VERSION 5.8 ;
BUSBITCHARS "[]" ;
DIVIDERCHAR "/" ;
UNITS
    DATABASE MICRONS 1000 ;
END UNITS

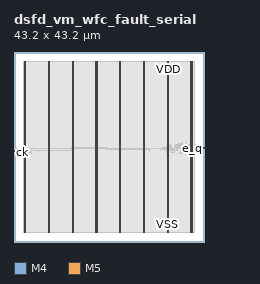
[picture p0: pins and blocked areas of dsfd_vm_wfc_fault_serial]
MACRO dsfd_vm_wfc_fault_serial
  FOREIGN dsfd_vm_wfc_fault_serial 0 0 ;
  CLASS BLOCK ;
  SIZE 43.2 BY 43.2 ;
  PIN ck
    DIRECTION INPUT ;
    USE SIGNAL ;
    PORT
      LAYER M4 ;
        RECT  0 20.4 0.084 20.424 ;
    END
  END ck
  PIN e_q
    DIRECTION OUTPUT ;
    USE SIGNAL ;
    PORT
      LAYER M4 ;
        RECT  43.116 21.36 43.2 21.384 ;
    END
  END e_q
  PIN g_q
    DIRECTION OUTPUT ;
    USE SIGNAL ;
    PORT
      LAYER M4 ;
        RECT  43.116 21.456 43.2 21.48 ;
    END
  END g_q
  PIN remote_fault
    DIRECTION INPUT ;
    USE SIGNAL ;
    PORT
      LAYER M4 ;
        RECT  0 20.496 0.084 20.52 ;
    END
  END remote_fault
  PIN rn
    DIRECTION INPUT ;
    USE SIGNAL ;
    PORT
      LAYER M4 ;
        RECT  0 20.592 0.084 20.616 ;
    END
  END rn
  PIN serial_fault
    DIRECTION INPUT ;
    USE SIGNAL ;
    PORT
      LAYER M4 ;
        RECT  0 20.688 0.084 20.712 ;
    END
  END serial_fault
  PIN source_fault
    DIRECTION OUTPUT ;
    USE SIGNAL ;
    PORT
      LAYER M4 ;
        RECT  43.116 21.552 43.2 21.576 ;
    END
  END source_fault
  PIN transfer_fault
    DIRECTION INPUT ;
    USE SIGNAL ;
    PORT
      LAYER M4 ;
        RECT  0 20.784 0.084 20.808 ;
    END
  END transfer_fault
  PIN VDD
    DIRECTION INOUT ;
    USE POWER ;
    PORT
      LAYER M5 ;
        RECT  40.392 2.151 40.512 41.049 ;
        RECT  34.992 2.151 35.112 41.049 ;
        RECT  29.592 2.151 29.712 41.049 ;
        RECT  24.192 2.151 24.312 41.049 ;
        RECT  18.792 2.151 18.912 41.049 ;
        RECT  13.392 2.151 13.512 41.049 ;
        RECT  7.992 2.151 8.112 41.049 ;
        RECT  2.592 2.151 2.712 41.049 ;
    END
  END VDD
  PIN VSS
    DIRECTION INOUT ;
    USE GROUND ;
    PORT
      LAYER M5 ;
        RECT  40.2 2.137 40.32 41.063 ;
        RECT  34.8 2.137 34.92 41.063 ;
        RECT  29.4 2.137 29.52 41.063 ;
        RECT  24 2.137 24.12 41.063 ;
        RECT  18.6 2.137 18.72 41.063 ;
        RECT  13.2 2.137 13.32 41.063 ;
        RECT  7.8 2.137 7.92 41.063 ;
        RECT  2.4 2.137 2.52 41.063 ;
    END
  END VSS
  # OT_OBS_CLOSED layer=M5 d_um=1.536 added=0
  OBS
    LAYER RVTN ;
     RECT  2.16 2.16 41.04 2.295 ;
     RECT  2.16 2.565 41.04 2.835 ;
     RECT  2.16 3.105 41.04 3.375 ;
     RECT  2.16 3.645 41.04 3.915 ;
     RECT  2.16 4.185 41.04 4.455 ;
     RECT  2.16 4.725 41.04 4.995 ;
     RECT  2.16 5.265 41.04 5.535 ;
     RECT  2.16 5.805 41.04 6.075 ;
     RECT  2.16 6.345 41.04 6.615 ;
     RECT  2.16 6.885 41.04 7.155 ;
     RECT  2.16 7.425 41.04 7.695 ;
     RECT  2.16 7.965 41.04 8.235 ;
     RECT  2.16 8.505 41.04 8.775 ;
     RECT  2.16 9.045 41.04 9.315 ;
     RECT  2.16 9.585 41.04 9.855 ;
     RECT  2.16 10.125 41.04 10.395 ;
     RECT  2.16 10.665 41.04 10.935 ;
     RECT  2.16 11.205 41.04 11.475 ;
     RECT  2.16 11.745 41.04 12.015 ;
     RECT  2.16 12.285 41.04 12.555 ;
     RECT  2.16 12.825 41.04 13.095 ;
     RECT  2.16 13.365 41.04 13.635 ;
     RECT  2.16 13.905 41.04 14.175 ;
     RECT  2.16 14.445 41.04 14.715 ;
     RECT  2.16 14.985 41.04 15.255 ;
     RECT  2.16 15.525 41.04 15.795 ;
     RECT  2.16 16.065 41.04 16.335 ;
     RECT  2.16 16.605 41.04 16.875 ;
     RECT  2.16 17.145 41.04 17.415 ;
     RECT  2.16 17.685 41.04 17.955 ;
     RECT  2.16 18.225 41.04 18.495 ;
     RECT  2.16 18.765 41.04 19.035 ;
     RECT  2.16 19.305 41.04 19.575 ;
     RECT  2.16 19.845 41.04 20.115 ;
     RECT  2.16 20.385 41.04 20.655 ;
     RECT  2.16 20.925 41.04 21.195 ;
     RECT  2.16 21.465 41.04 21.735 ;
     RECT  2.16 22.005 41.04 22.275 ;
     RECT  2.16 22.545 41.04 22.815 ;
     RECT  2.16 23.085 41.04 23.355 ;
     RECT  2.16 23.625 41.04 23.895 ;
     RECT  2.16 24.165 41.04 24.435 ;
     RECT  2.16 24.705 41.04 24.975 ;
     RECT  2.16 25.245 41.04 25.515 ;
     RECT  2.16 25.785 41.04 26.055 ;
     RECT  2.16 26.325 41.04 26.595 ;
     RECT  2.16 26.865 41.04 27.135 ;
     RECT  2.16 27.405 41.04 27.675 ;
     RECT  2.16 27.945 41.04 28.215 ;
     RECT  2.16 28.485 41.04 28.755 ;
     RECT  2.16 29.025 41.04 29.295 ;
     RECT  2.16 29.565 41.04 29.835 ;
     RECT  2.16 30.105 41.04 30.375 ;
     RECT  2.16 30.645 41.04 30.915 ;
     RECT  2.16 31.185 41.04 31.455 ;
     RECT  2.16 31.725 41.04 31.995 ;
     RECT  2.16 32.265 41.04 32.535 ;
     RECT  2.16 32.805 41.04 33.075 ;
     RECT  2.16 33.345 41.04 33.615 ;
     RECT  2.16 33.885 41.04 34.155 ;
     RECT  2.16 34.425 41.04 34.695 ;
     RECT  2.16 34.965 41.04 35.235 ;
     RECT  2.16 35.505 41.04 35.775 ;
     RECT  2.16 36.045 41.04 36.315 ;
     RECT  2.16 36.585 41.04 36.855 ;
     RECT  2.16 37.125 41.04 37.395 ;
     RECT  2.16 37.665 41.04 37.935 ;
     RECT  2.16 38.205 41.04 38.475 ;
     RECT  2.16 38.745 41.04 39.015 ;
     RECT  2.16 39.285 41.04 39.555 ;
     RECT  2.16 39.825 41.04 40.095 ;
     RECT  2.16 40.365 41.04 40.635 ;
     RECT  2.16 40.905 41.04 41.04 ;
    LAYER RVTP ;
     RECT  2.16 2.295 41.04 2.565 ;
     RECT  2.16 2.835 41.04 3.105 ;
     RECT  2.16 3.375 41.04 3.645 ;
     RECT  2.16 3.915 41.04 4.185 ;
     RECT  2.16 4.455 41.04 4.725 ;
     RECT  2.16 4.995 41.04 5.265 ;
     RECT  2.16 5.535 41.04 5.805 ;
     RECT  2.16 6.075 41.04 6.345 ;
     RECT  2.16 6.615 41.04 6.885 ;
     RECT  2.16 7.155 41.04 7.425 ;
     RECT  2.16 7.695 41.04 7.965 ;
     RECT  2.16 8.235 41.04 8.505 ;
     RECT  2.16 8.775 41.04 9.045 ;
     RECT  2.16 9.315 41.04 9.585 ;
     RECT  2.16 9.855 41.04 10.125 ;
     RECT  2.16 10.395 41.04 10.665 ;
     RECT  2.16 10.935 41.04 11.205 ;
     RECT  2.16 11.475 41.04 11.745 ;
     RECT  2.16 12.015 41.04 12.285 ;
     RECT  2.16 12.555 41.04 12.825 ;
     RECT  2.16 13.095 41.04 13.365 ;
     RECT  2.16 13.635 41.04 13.905 ;
     RECT  2.16 14.175 41.04 14.445 ;
     RECT  2.16 14.715 41.04 14.985 ;
     RECT  2.16 15.255 41.04 15.525 ;
     RECT  2.16 15.795 41.04 16.065 ;
     RECT  2.16 16.335 41.04 16.605 ;
     RECT  2.16 16.875 41.04 17.145 ;
     RECT  2.16 17.415 41.04 17.685 ;
     RECT  2.16 17.955 41.04 18.225 ;
     RECT  2.16 18.495 41.04 18.765 ;
     RECT  2.16 19.035 41.04 19.305 ;
     RECT  2.16 19.575 41.04 19.845 ;
     RECT  2.16 20.115 41.04 20.385 ;
     RECT  2.16 20.655 41.04 20.925 ;
     RECT  2.16 21.195 41.04 21.465 ;
     RECT  2.16 21.735 41.04 22.005 ;
     RECT  2.16 22.275 41.04 22.545 ;
     RECT  2.16 22.815 41.04 23.085 ;
     RECT  2.16 23.355 41.04 23.625 ;
     RECT  2.16 23.895 41.04 24.165 ;
     RECT  2.16 24.435 41.04 24.705 ;
     RECT  2.16 24.975 41.04 25.245 ;
     RECT  2.16 25.515 41.04 25.785 ;
     RECT  2.16 26.055 41.04 26.325 ;
     RECT  2.16 26.595 41.04 26.865 ;
     RECT  2.16 27.135 41.04 27.405 ;
     RECT  2.16 27.675 41.04 27.945 ;
     RECT  2.16 28.215 41.04 28.485 ;
     RECT  2.16 28.755 41.04 29.025 ;
     RECT  2.16 29.295 41.04 29.565 ;
     RECT  2.16 29.835 41.04 30.105 ;
     RECT  2.16 30.375 41.04 30.645 ;
     RECT  2.16 30.915 41.04 31.185 ;
     RECT  2.16 31.455 41.04 31.725 ;
     RECT  2.16 31.995 41.04 32.265 ;
     RECT  2.16 32.535 41.04 32.805 ;
     RECT  2.16 33.075 41.04 33.345 ;
     RECT  2.16 33.615 41.04 33.885 ;
     RECT  2.16 34.155 41.04 34.425 ;
     RECT  2.16 34.695 41.04 34.965 ;
     RECT  2.16 35.235 41.04 35.505 ;
     RECT  2.16 35.775 41.04 36.045 ;
     RECT  2.16 36.315 41.04 36.585 ;
     RECT  2.16 36.855 41.04 37.125 ;
     RECT  2.16 37.395 41.04 37.665 ;
     RECT  2.16 37.935 41.04 38.205 ;
     RECT  2.16 38.475 41.04 38.745 ;
     RECT  2.16 39.015 41.04 39.285 ;
     RECT  2.16 39.555 41.04 39.825 ;
     RECT  2.16 40.095 41.04 40.365 ;
     RECT  2.16 40.635 41.04 40.905 ;
    LAYER M1 ;
     RECT  2.16 2.151 41.04 41.049 ;
    LAYER M2 ;
     RECT  2.16 2.151 41.04 41.049 ;
     RECT  41.04 21.006 42.179 21.294 ;
     RECT  41.04 22.176 42.179 22.194 ;
     RECT  42.179 21.006 42.215 21.024 ;
    LAYER M3 ;
     RECT  2.415 2.143 2.505 2.413 ;
     RECT  7.815 2.143 7.905 2.413 ;
     RECT  13.215 2.143 13.305 2.413 ;
     RECT  18.615 2.143 18.705 2.413 ;
     RECT  24.015 2.143 24.105 2.413 ;
     RECT  29.415 2.143 29.505 2.413 ;
     RECT  34.815 2.143 34.905 2.413 ;
     RECT  40.215 2.143 40.305 2.413 ;
     RECT  38.952 19.885 38.97 19.921 ;
     RECT  38.952 19.921 39.042 20.119 ;
     RECT  38.628 20.119 39.042 20.155 ;
     RECT  38.412 20.155 39.042 20.191 ;
     RECT  2.415 2.413 2.697 20.317 ;
     RECT  37.692 20.191 39.042 20.317 ;
     RECT  2.415 20.317 3.294 20.353 ;
     RECT  4.068 20.317 4.086 20.353 ;
     RECT  34.815 2.413 35.097 20.353 ;
     RECT  37.692 20.317 39.294 20.417 ;
     RECT  2.415 20.353 4.086 20.425 ;
     RECT  35.928 20.353 35.946 20.425 ;
     RECT  35.928 20.425 36.486 20.461 ;
     RECT  37.836 20.417 39.294 20.461 ;
     RECT  40.215 2.413 40.497 20.461 ;
     RECT  34.776 20.353 35.097 20.695 ;
     RECT  35.892 20.461 36.486 20.695 ;
     RECT  2.304 20.425 4.086 20.731 ;
     RECT  34.776 20.695 36.486 20.731 ;
     RECT  2.304 20.731 4.554 20.821 ;
     RECT  13.215 2.413 13.497 20.821 ;
     RECT  34.776 20.731 36.918 20.821 ;
     RECT  2.304 20.821 4.878 20.857 ;
     RECT  5.796 20.659 5.814 20.857 ;
     RECT  33.336 20.731 33.354 20.857 ;
     RECT  2.304 20.857 5.814 20.861 ;
     RECT  2.304 20.861 4.266 20.885 ;
     RECT  5.58 20.861 5.814 20.893 ;
     RECT  33.228 20.857 33.354 20.957 ;
     RECT  2.34 20.885 4.266 21.029 ;
     RECT  5.58 20.893 6.174 21.029 ;
     RECT  29.415 2.413 29.697 21.115 ;
     RECT  33.84 21.001 33.858 21.115 ;
     RECT  34.776 20.821 37.062 21.115 ;
     RECT  2.34 21.029 4.086 21.155 ;
     RECT  5.58 21.029 5.598 21.155 ;
     RECT  28.908 21.115 29.697 21.155 ;
     RECT  21.132 21.115 21.15 21.163 ;
     RECT  20.916 21.163 21.15 21.2 ;
     RECT  33.84 21.115 37.062 21.235 ;
     RECT  37.836 20.461 40.497 21.235 ;
     RECT  30.78 20.659 30.798 21.245 ;
     RECT  42.192 21.001 42.21 21.271 ;
     RECT  14.22 21.091 14.238 21.293 ;
     RECT  33.84 21.235 40.698 21.299 ;
     RECT  33.84 21.299 35.766 21.389 ;
     RECT  13.104 20.821 13.497 21.485 ;
     RECT  14.724 21.355 14.85 21.485 ;
     RECT  21.132 21.2 21.15 21.485 ;
     RECT  42.156 21.271 42.21 21.485 ;
     RECT  36.504 21.299 40.698 21.569 ;
     RECT  34.74 21.389 35.766 21.659 ;
     RECT  36.576 21.569 40.698 21.803 ;
     RECT  36.612 21.803 40.698 21.929 ;
     RECT  34.815 21.659 35.766 21.965 ;
     RECT  36.648 21.929 40.698 22.073 ;
     RECT  37.008 22.073 40.698 22.109 ;
     RECT  34.815 21.965 35.694 22.199 ;
     RECT  42.156 21.485 42.174 22.199 ;
     RECT  34.815 22.199 35.586 22.235 ;
     RECT  39.24 22.109 40.698 22.235 ;
     RECT  37.008 22.109 38.394 22.271 ;
     RECT  37.512 22.271 38.394 22.307 ;
     RECT  37.692 22.307 38.394 22.469 ;
     RECT  38.232 22.469 38.394 22.505 ;
     RECT  38.376 22.505 38.394 22.739 ;
     RECT  39.24 22.235 39.258 22.739 ;
     RECT  2.415 21.155 2.697 40.787 ;
     RECT  7.815 2.413 8.097 40.787 ;
     RECT  13.215 21.485 13.497 40.787 ;
     RECT  18.615 2.413 18.897 40.787 ;
     RECT  24.015 2.413 24.297 40.787 ;
     RECT  29.415 21.155 29.697 40.787 ;
     RECT  34.815 22.235 35.097 40.787 ;
     RECT  40.215 22.235 40.497 40.787 ;
     RECT  2.415 40.787 2.505 41.057 ;
     RECT  7.815 40.787 7.905 41.057 ;
     RECT  13.215 40.787 13.305 41.057 ;
     RECT  18.615 40.787 18.705 41.057 ;
     RECT  24.015 40.787 24.105 41.057 ;
     RECT  29.415 40.787 29.505 41.057 ;
     RECT  34.815 40.787 34.905 41.057 ;
     RECT  40.215 40.787 40.305 41.057 ;
    LAYER M4 ;
     RECT  0.084 20.4 0.133 20.424 ;
     RECT  0.06 20.424 0.133 20.496 ;
     RECT  0.084 20.496 0.133 20.52 ;
     RECT  0.06 20.52 0.133 20.592 ;
     RECT  0.084 20.592 0.133 20.616 ;
     RECT  0.06 20.616 0.133 20.688 ;
     RECT  0.084 20.688 0.133 20.712 ;
     RECT  0.06 20.712 0.133 20.784 ;
     RECT  0.084 20.784 0.133 20.808 ;
     RECT  0.133 20.4 0.179 21.192 ;
     RECT  0.179 20.496 2.408 21.192 ;
     RECT  2.408 2.148 2.512 41.052 ;
     RECT  2.512 2.418 2.704 40.782 ;
     RECT  2.704 20.688 2.801 21.192 ;
     RECT  2.801 20.832 7.808 21.192 ;
     RECT  7.808 2.148 7.912 41.052 ;
     RECT  7.912 2.418 8.104 40.782 ;
     RECT  8.104 20.832 13.093 21.192 ;
     RECT  13.093 20.832 13.208 21.48 ;
     RECT  13.208 2.148 13.312 41.052 ;
     RECT  13.312 2.418 13.504 40.782 ;
     RECT  13.504 21.168 18.608 21.48 ;
     RECT  18.608 2.148 18.712 41.052 ;
     RECT  18.712 2.418 18.904 40.782 ;
     RECT  18.904 21.168 21.121 21.48 ;
     RECT  21.121 21.12 21.161 21.48 ;
     RECT  21.161 21.12 24.008 21.288 ;
     RECT  24.008 2.148 24.112 41.052 ;
     RECT  24.112 2.418 24.304 40.782 ;
     RECT  24.304 21.12 29.408 21.288 ;
     RECT  29.408 2.148 29.512 41.052 ;
     RECT  29.512 2.418 29.704 40.782 ;
     RECT  29.704 21.12 30.809 21.288 ;
     RECT  30.809 21.216 34.297 21.288 ;
     RECT  34.297 21.12 34.808 21.288 ;
     RECT  34.808 2.148 34.912 41.052 ;
     RECT  34.912 2.418 35.104 40.782 ;
     RECT  35.104 21.12 36.277 21.24 ;
     RECT  36.277 21.072 36.385 21.24 ;
     RECT  36.385 20.832 36.997 21.24 ;
     RECT  36.997 20.832 37.001 21.672 ;
     RECT  37.001 21.072 37.073 21.672 ;
     RECT  37.073 21.648 38.369 21.672 ;
     RECT  40.208 2.148 40.312 41.052 ;
     RECT  40.312 2.418 40.504 40.782 ;
     RECT  42.145 21.36 43.116 21.384 ;
     RECT  42.145 21.384 43.164 21.456 ;
     RECT  42.145 21.456 43.116 21.48 ;
     RECT  42.145 21.48 43.164 21.552 ;
     RECT  42.145 21.552 43.116 21.576 ;
    LAYER M5 ;
     RECT  2.4 2.137 2.52 2.151 ;
     RECT  7.8 2.137 7.92 2.151 ;
     RECT  13.2 2.137 13.32 2.151 ;
     RECT  18.6 2.137 18.72 2.151 ;
     RECT  24 2.137 24.12 2.151 ;
     RECT  29.4 2.137 29.52 2.151 ;
     RECT  34.8 2.137 34.92 2.151 ;
     RECT  40.2 2.137 40.32 2.151 ;
     RECT  0.144 20.389 0.168 21.203 ;
     RECT  2.4 2.151 2.712 41.049 ;
     RECT  7.8 2.151 8.112 41.049 ;
     RECT  13.2 2.151 13.512 41.049 ;
     RECT  18.6 2.151 18.912 41.049 ;
     RECT  24 2.151 24.312 41.049 ;
     RECT  29.4 2.151 29.712 41.049 ;
     RECT  34.8 2.151 35.112 41.049 ;
     RECT  40.2 2.151 40.512 41.049 ;
     RECT  2.4 41.049 2.52 41.063 ;
     RECT  7.8 41.049 7.92 41.063 ;
     RECT  13.2 41.049 13.32 41.063 ;
     RECT  18.6 41.049 18.72 41.063 ;
     RECT  24 41.049 24.12 41.063 ;
     RECT  29.4 41.049 29.52 41.063 ;
     RECT  34.8 41.049 34.92 41.063 ;
     RECT  40.2 41.049 40.32 41.063 ;
  END
END dsfd_vm_wfc_fault_serial
END LIBRARY
